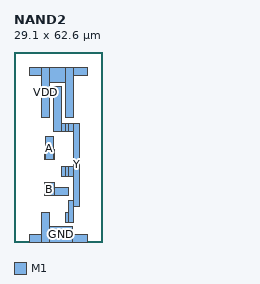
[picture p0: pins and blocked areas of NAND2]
MACRO NAND2
  CLASS CORE ;
  ORIGIN 0 0 ;
  SIZE 29.100 BY 62.600 ;
  SYMMETRY X Y ;
  SITE TR1um_site ;
  PIN GND
    DIRECTION INOUT ;
    USE GROUND ;
    PORT
      LAYER M1 ;
        RECT 5.000 0.000 9.100 2.600 ;
      LAYER M1 ;
        RECT 9.100 0.000 11.700 9.800 ;
      LAYER M1 ;
        RECT 11.700 0.000 19.300 5.000 ;
      LAYER M1 ;
        RECT 19.300 0.000 24.100 2.600 ;
    END
  END GND
  PIN Y
    DIRECTION OUTPUT ;
    USE SIGNAL ;
    PORT
      LAYER M1 ;
        RECT 13.100 36.400 15.600 51.200 ;
      LAYER M1 ;
        RECT 15.600 21.600 15.700 25.000 ;
      LAYER M1 ;
        RECT 15.600 36.400 15.700 51.200 ;
      LAYER M1 ;
        RECT 15.700 21.600 17.100 25.000 ;
      LAYER M1 ;
        RECT 15.700 36.400 17.100 39.000 ;
      LAYER M1 ;
        RECT 17.100 6.400 17.900 9.800 ;
      LAYER M1 ;
        RECT 17.100 21.600 17.900 25.000 ;
      LAYER M1 ;
        RECT 17.100 36.400 17.900 39.000 ;
      LAYER M1 ;
        RECT 17.900 6.400 19.700 13.600 ;
      LAYER M1 ;
        RECT 17.900 21.600 19.700 25.000 ;
      LAYER M1 ;
        RECT 17.900 36.400 19.700 39.000 ;
      LAYER M1 ;
        RECT 19.700 11.800 21.500 39.000 ;
    END
  END Y
  PIN B
    DIRECTION INPUT ;
    USE SIGNAL ;
    PORT
      LAYER M1 ;
        RECT 10.100 15.300 13.500 19.500 ;
      LAYER M1 ;
        RECT 13.500 15.300 18.100 17.900 ;
    END
  END B
  PIN A
    DIRECTION INPUT ;
    USE SIGNAL ;
    PORT
      LAYER M1 ;
        RECT 10.100 27.100 10.300 30.500 ;
      LAYER M1 ;
        RECT 10.300 27.100 12.900 34.800 ;
      LAYER M1 ;
        RECT 12.900 27.100 13.500 30.500 ;
    END
  END A
  PIN VDD
    DIRECTION INOUT ;
    USE POWER ;
    PORT
      LAYER M1 ;
        RECT 5.000 55.000 9.100 57.600 ;
      LAYER M1 ;
        RECT 9.100 41.000 11.700 57.600 ;
      LAYER M1 ;
        RECT 11.700 52.600 17.100 57.600 ;
      LAYER M1 ;
        RECT 17.100 41.000 19.700 57.600 ;
      LAYER M1 ;
        RECT 19.700 55.000 24.100 57.600 ;
    END
  END VDD
END NAND2
